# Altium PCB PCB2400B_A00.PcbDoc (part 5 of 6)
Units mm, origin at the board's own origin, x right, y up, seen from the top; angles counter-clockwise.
Board outline 114.9 x 59.9 mm, 6 copper layers (Top Layer, Signal Layer 2, Signal Layer 3, Signal Layer 4, Signal Layer 5, Bottom Layer), stack 1.555 mm thick; 383 components, 308 nets, 1386 pads, 1147 vias.

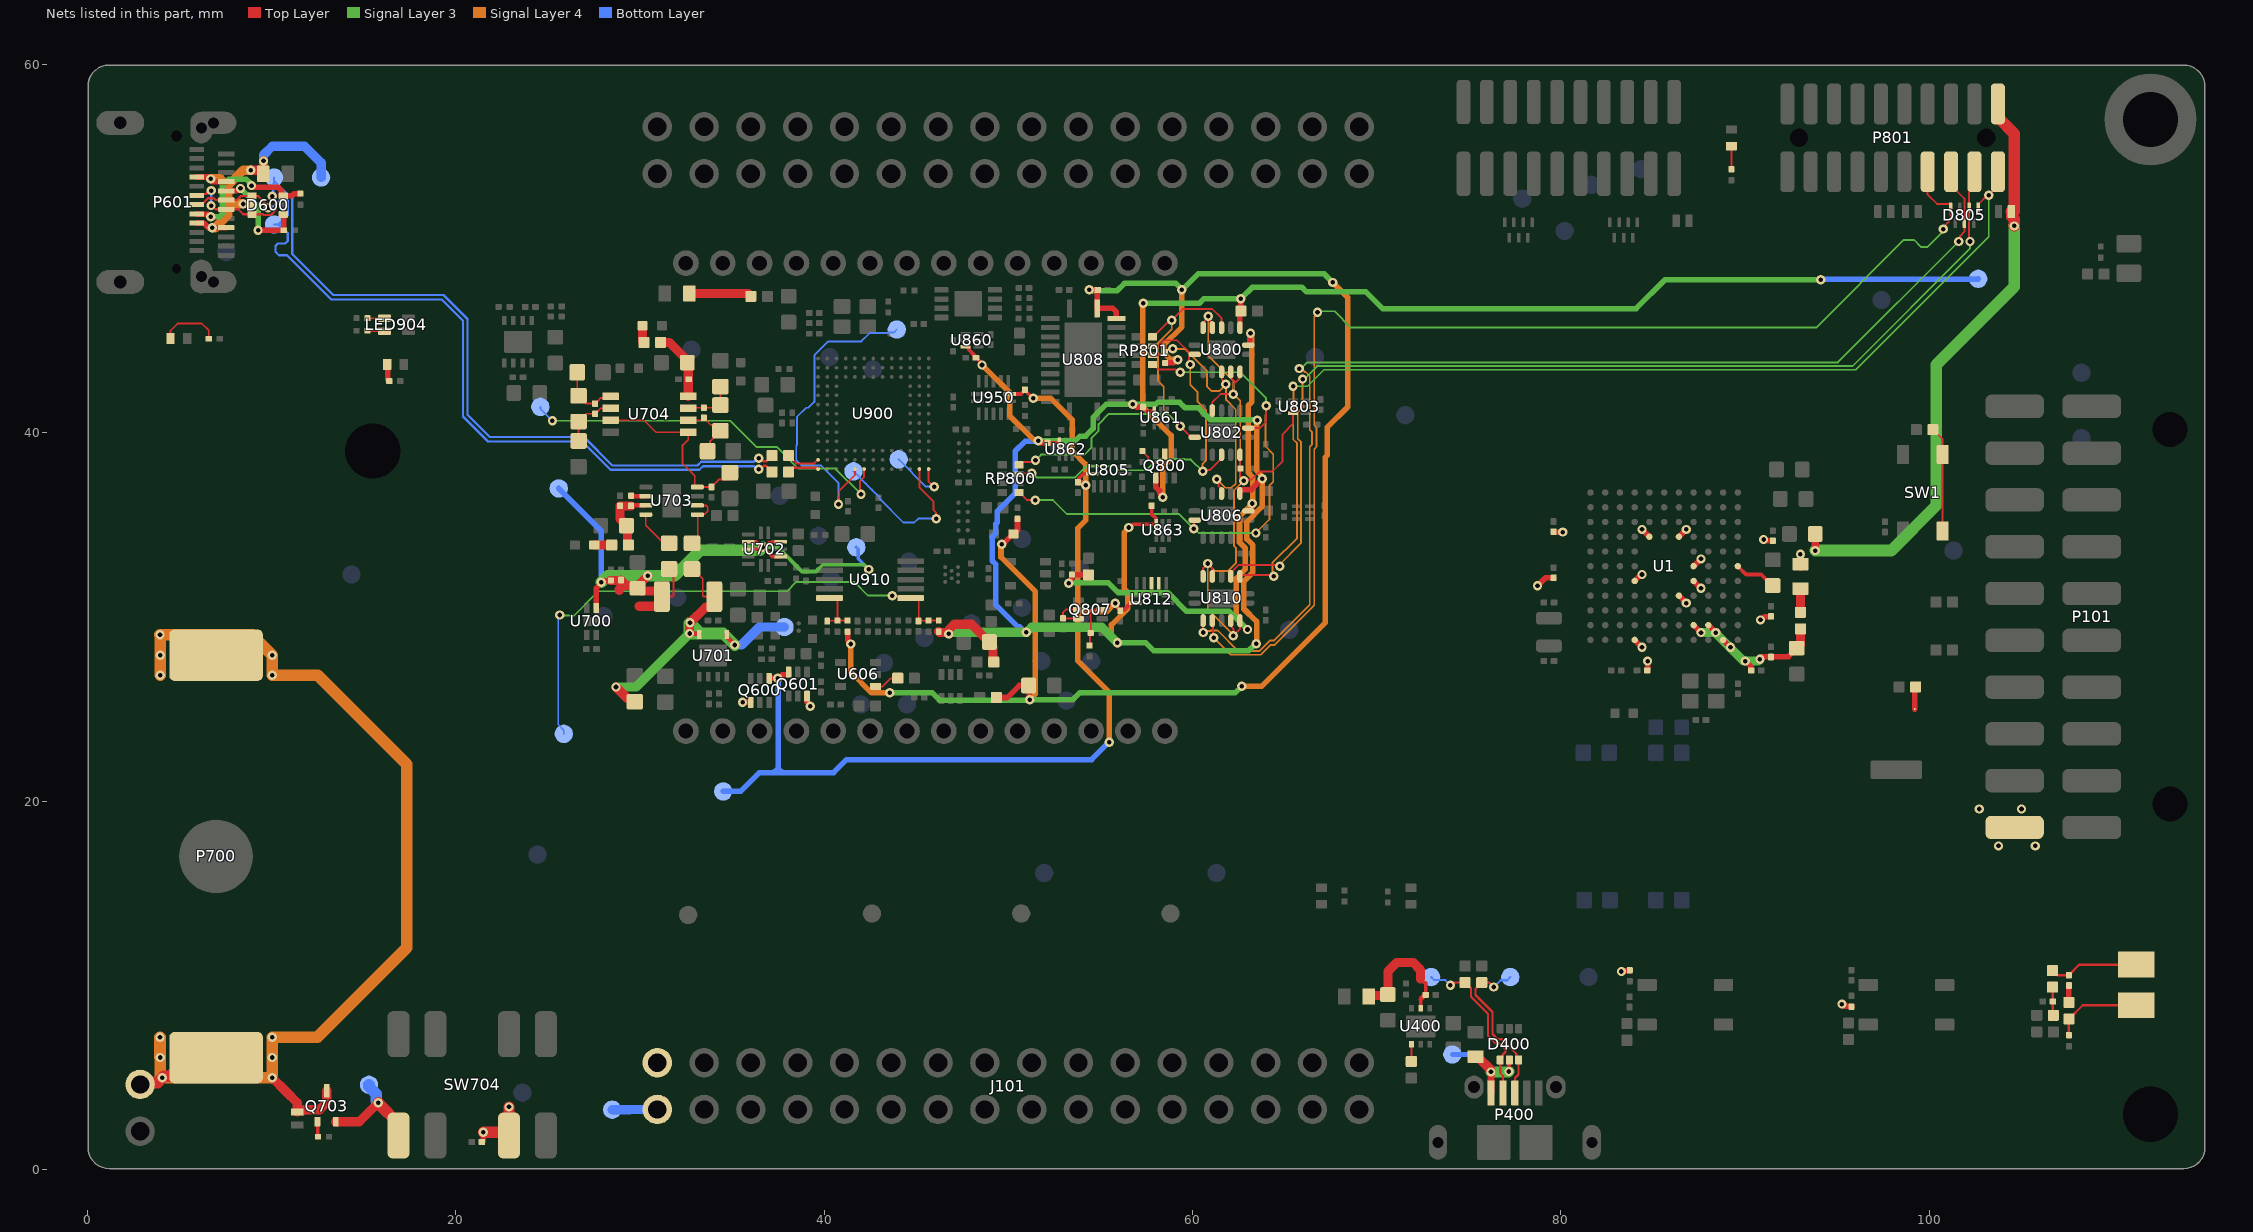
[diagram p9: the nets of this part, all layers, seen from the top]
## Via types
v1: diameter 0.5, hole 0.25, Top Layer to Bottom Layer, tented both sides, 768 vias
v2: diameter 0.508, hole 0.25, Top Layer to Bottom Layer, tented both sides, 379 vias

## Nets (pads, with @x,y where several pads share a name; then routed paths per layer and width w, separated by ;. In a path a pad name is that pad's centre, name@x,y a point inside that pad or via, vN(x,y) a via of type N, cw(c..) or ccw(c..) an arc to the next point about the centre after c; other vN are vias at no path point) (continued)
N16939638: TPJ900.1 U900.A2 | length 8.8
  Top Layer w0.1: U900.A2@45.175,38.025 45.175,37.031 45.741,36.466 45.947,36.259 45.947,35.803 46.07,35.68 46.07,35.35 v2(46.086,35.334)
  Bottom Layer w0.1: TPJ900.1@41.607,37.9 42.27,37.237 42.6,36.907 43.018,36.488 43.018,36.464 43.018,36.409 44.305,35.122 44.897,35.122 45.109,35.334 v2(46.086,35.334)
N16939640: TPJ901.1 U900.A1 | length 3.6
  Top Layer w0.1: U900.A1@45.675,37.966 45.675,37.346 45.934,37.088 45.934,37.072 v2(45.972,37.072)
  Bottom Layer w0.1: TPJ901.1@44.05,38.55 45.53,37.07 45.905,37.07 45.925,37.05 45.947,37.072 v2(45.972,37.072)
N16940103: TPJ908.1 U900.A9 | length 17.6
  Top Layer w0.1: v2@40.781,36.128 40.786,36.134 40.786,36.466 40.827,36.507 40.827,36.839 ; 40.96,36.971 40.827,36.839 ; U900.A9@41.675,38.025 41.675,37.687 40.827,36.839
  Bottom Layer w0.1: v2(40.786,36.123) 40.786,37.253 39.816,38.223 38.777,38.223 38.489,38.511 38.489,39.301 38.525,39.337 38.525,40.85 39.025,41.35 39.154,41.35 39.475,41.671 39.475,44.2 40.225,44.95 42.025,44.95 42.485,45.41 43.441,45.41 43.46,45.428 43.778,45.428 TPJ908.1@43.95,45.6
N16942491: R902.2 U900.B13 | length 1.9
  Top Layer w0.12: R902.2@38.075,38.75 38.493,38.332 39.472,38.332 39.666,38.525 U900.B13@39.675,38.525
N16942503: R904.2 U900.A13 | length 1.7
  Top Layer w0.12: R904.2@38.075,37.875 38.292,38.092 39.587,38.092 39.653,38.025 U900.A13@39.675,38.025
N16943456: TPJ902.1 U900.A8 | length 20.9
  Top Layer w0.1: v2(42.007,36.66) 41.95,36.717 41.95,37.375 42.175,37.6 U900.A8@42.175,38.025
  Signal Layer 3 w0.1: v1(25.254,40.644) 34.906,40.644 36.325,39.225 37.425,39.225 38.6,38.05 40.618,38.05 v2@42.007,36.661
  Bottom Layer w0.1: TPJ902.1@24.6,41.4 24.6,41.298 v1(25.254,40.644)
N16944010: LED903.2 R912.2 | length 0.7
  Top Layer w0.305: LED903.2@16.325,43.5 16.325,42.875 16.382,42.818 16.382,42.808 16.39,42.8 R912.2@16.4,42.8
N16966205: LED904.2 R920.2 | length 0.9
  Top Layer w0.1: R920.2@15.222,46.215 15.237,46.2 15.425,46.2 15.435,46.21 LED904.2@16.139,46.21
N16966207: LED904.1 R919.2 | length 0.9
  Top Layer w0.1: R919.2@15.222,45.531 15.228,45.525 15.45,45.525 15.465,45.51 LED904.1@16.139,45.51
N16966211: LED901.1 R903.2 | length 3.3
  Top Layer w0.1: LED901.1@4.525,45.125 4.525,45.538 4.912,45.925 6.225,45.925 6.6,45.55 R903.2@6.6,45.1
N16966215: LED900.1 R900.2 | length 1.3
  Top Layer w0.1: R900.2@89.25,54.3 LED900.1@89.25,55.55
N16996446: Q807.5 Q807.6 R838.1 | length 2
  Top Layer w0.1: Q807.6@53.8,29.9 53.787,29.913 52.987,29.913 R838.1@52.975,29.925 52.975,30.245 53.13,30.4 Q807.5@53.8,30.4
N16997087: Q807.2 R839.2 R841.1 | length 2.5
  Top Layer w0.1: R841.1@54.411,28.445 54.443,28.477 54.443,29.093 R839.2@54.475,29.125 54.475,30.2 54.675,30.4 Q807.2@55.1,30.4
N17012885: L900.2 R130.1 | length 3.3
  Top Layer w0.5: L900.2@32.69,47.55 35.875,47.55 R130.1@35.975,47.45
N17206837: C198.1 L100.1 R197.2 | length 4.9
  Top Layer w0.127: R197.2@106.677,10.8 106.933,10.544 C198.1@107.568,10.544 107.568,10.564 108.129,11.125 L100.1@111.222,11.125
N17206841: L100.2 R195.1 R196.2 | length 4.8
  Top Layer w0.127: R196.2@107.568,7.293 107.568,8.171 R195.1@107.572,8.175 108.322,8.925 L100.2@111.222,8.925
N17206845: C198.2 R195.2 | length 0.9
  Top Layer w0.3: C198.2@107.568,9.994 107.57,9.992 107.57,9.077 R195.2@107.572,9.075
N17206847: C199.1 R197.1 R198.2 | length 1.5
  Top Layer w0.127: R197.1@106.677,9.9 106.7,9.877 C199.1@106.7,9.126 106.7,8.397 R198.2@106.722,8.375
N17234269: C200.1 R246.2 | length 1.2
  Top Layer w0.3: C200.1@99.2,25 99.2,26.15 R246.2@99.25,26.2
N17262372: C729.1 R718.2 U703.4 U704.3 U704.5 | length 9.9
  Top Layer w0.1: U704.3@28.42,40.675 30.227,40.675 30.877,40.025 U704.5@32.631,40.025 32.631,39.627 32.325,39.321 32.325,38.325 32.983,37.667 32.983,37.124 33.057,37.05 U703.4@33.125,37.05 C729.1@33.9,37.05 33.9,37.07 34.28,37.45 R718.2@34.925,37.45
N17262509: R709.1 U703.1 U703.2 | length 3.2
  Top Layer w0.1: R709.1@32.832,34 33.147,34.315 33.147,35.528 U703.1@33.125,35.55 33.163,35.588 33.537,35.588 33.687,35.738 33.687,35.96 33.597,36.05 U703.2@33.125,36.05
N17262517: C710.2 U703.6 | length 0.8
  Top Layer w0.25: C710.2@29.525,36.575 29.55,36.55 U703.6@30.325,36.55
N17262549: R710.1 U703.8 | length 2.2
  Top Layer w0.1: U703.8@30.325,35.55 30.325,34.975 R710.1@31.3,34
  Top Layer w0.127: R710.1@31.3,34 R710.1@31.59,34
N17262561: L700.2 R717.1 | length 1
  Top Layer w0.5: L700.2@27.525,33.9 R717.1@28.475,33.9
N17262689: C766.1 R765.1 R767.2 U704.2 | length 3.1
  Top Layer w0.1: R767.2@26.675,39.55 R765.1@26.675,40.6 27.1,41.025 C766.1@27.575,41.025 27.875,41.325 U704.2@28.42,41.325
N17262695: C766.2 R764.1 R765.2 U704.1 | length 3.4
  Top Layer w0.1: R764.1@26.6,43.275 26.6,42.075 R765.2@26.675,42 27.1,41.575 C766.2@27.575,41.575 27.575,41.595 27.685,41.705 27.705,41.705 27.884,41.884 28.328,41.884 U704.1@28.42,41.975
N17262717: C770.1 R769.1 R771.2 U704.6 | length 3.5
  Top Layer w0.1: U704.6@32.631,40.675 33.35,40.675 C770.1@33.475,40.8 33.475,40.78 33.585,40.67 33.605,40.67 33.863,40.412 34.063,40.412 R769.1@34.375,40.1 33.816,39.541 33.816,39.141 R771.2@33.675,39
N17262723: C770.2 R768.1 R769.2 U704.7 | length 2.8
  Top Layer w0.1: U704.7@32.631,41.325 32.656,41.35 C770.2@33.475,41.35 34.225,41.35 R769.2@34.375,41.5 R768.1@34.375,42.5
N17263058: C730.1 C731.1 R731.1 U704.8 | length 3.9
  Top Layer w0.5: R731.1@31.125,44.9 31.6,44.9 32.575,43.925 C731.1@32.575,43.8 32.63,43.745 32.63,42.031 32.575,42.031 U704.8@32.631,41.975
N17263074: L704.2 R731.2 | length 0.9
  Top Layer w0.5: L704.2@30.15,45.8 30.15,44.975 R731.2@30.225,44.9
N17356200: Q800.2 R815.1 | length 1.9
  Top Layer w0.1: R815.1@57.276,39.006 57.276,38.996 57.605,38.667 57.605,38.57 57.825,38.35 58.175,38.35 58.5,38.675 Q800.2@58.5,38.85
N17454530: D703.1 P700.1 Q703.3 ST701.2 | length 60.2
  Top Layer w0.508: v2(10.046,4.981) 10.793,4.234 11.403,3.625 D703.1@11.403,3.123 11.457,3.177 11.701,3.177 11.772,3.249 12.618,3.249 13,3.631 Q703.3@13,4.275
  Top Layer w0.635: ST701.2@2.875,4.62 2.98,4.725 3.83,4.725 v2(4.087,4.981) 4.166,5.061 4.521,5.061 5.538,6.078 8,6.078 P700.1@8.328,5.75 ; P700.1@7.846,27.922 P700.1@8.067,28.143
  Signal Layer 4 w0.635: v2(3.958,7.181) 3.958,6.085 v2(3.962,6.081) 3.962,5.106 v2(4.087,4.981) v2(10.046,4.981) v2(10.046,6.081) v2(10.046,7.181) 12.5,7.181 17.352,12.033 17.352,21.996 12.523,26.825 v2(10.046,26.825) v2(10.046,27.925) 8.946,29.025 v2(3.958,29.025) 3.962,29.021 v2(3.962,27.925) v2(3.962,26.825)
N17454556: Q703.2 SW704.1 TP156.1 | length 6
  Top Layer w0.508: Q703.2@13.5,2.6 14.775,2.6 v1(15.8,3.625)
  Top Layer w0.635: v1(15.8,3.625) 15.8,3.6 16.9,2.5 16.9,2.325 SW704.1@16.9,1.85
  Bottom Layer w0.635: TP156.1@15.3,4.6 15.3,4.501 15.7,4.101 v1@15.7,3.725
N17454707: Q703.1 R792.2 | length 0.8
  Top Layer w0.203: Q703.1@12.5,2.6 12.517,2.583 12.517,1.799 R792.2@12.534,1.782
N17455720: L1.2 R2.1 | length 1.2
  Top Layer w0.5: L1.2@92.975,31.45 93,31.425 R2.1@93,30.25
N17455730: C3.1 C4.1 C5.1 R2.2 U1.K8 U1.K9 U1.L10 | length 9.7
  Top Layer w0.3: U1.K8@87.2,29.55 v1(87.601,29.149) ; U1.K9@88,29.55 v1(88.401,29.149) ; U1.L10@88.8,28.75 v1(89.201,28.349) ; v1(90,27.6) 90.019,27.6 90.295,27.324 90.295,27.11 90.305,27.1 C4.1@90.325,27.1 ; v1(90.8,27.7) 90.925,27.825 C5.1@91.4,27.825 91.475,27.825 92.325,27.825 ; 92.35,27.85 92.325,27.825 ; C3.1@92.8,28.3 92.325,27.825
  Top Layer w0.5: C3.1@92.8,28.3 93,28.5 R2.2@93,29.35
  Signal Layer 3 w0.5: v1(87.601,29.149) v1(88.401,29.149) 88.401,29.116 89.917,27.6 v1(90,27.6) 90.7,27.6 v1(90.8,27.7)
N17455955: C16.1 U1.F11 | length 2.4
  Top Layer w0.203: U1.F11@89.6,32.75 90.05,32.3 90.875,32.3 91.47,31.705 C16.1@91.52,31.705
N17456044: R7.2 SW1.3 SW1.4 | length 5.7
  Top Layer w0.1: R7.2@100.187,40.162 100.717,39.631 SW1.4@100.717,38.814 SW1.3@100.717,34.664
N17457251: D400.6 P400.3 R405.1 TPJ403.1 | length 9.2
  Top Layer w0.12: v1(76.351,9.911) 76.112,10.15 R405.1@75.7,10.15 75.36,9.81 75.36,9.475 76.281,8.554 76.281,7.363 76.57,7.074 76.788,7.074 77.572,6.289 77.572,6.077 D400.6@77.7,5.95 77.7,5.16 77.508,4.968 77.508,4.165 P400.3@77.5,4.157
  Bottom Layer w0.12: v1@76.35,9.9 76.728,10.278 77.079,10.278 TPJ403.1@77.25,10.449
N17457255: D400.4 P400.2 R406.1 TPJ404.1 | length 9.3
  Top Layer w0.12: v1(74,10) 74.103,10 74.253,10.15 R406.1@74.8,10.15 75.12,9.83 75.12,9.375 76.041,8.455 76.041,7.264 76.471,6.834 76.689,6.834 76.99,6.533 76.99,6.382 76.827,6.22 76.827,6.077 D400.4@76.7,5.95 76.7,5.236 76.85,5.085 P400.2@76.85,4.157
  Bottom Layer w0.12: TPJ404.1@72.95,10.449 73.115,10.284 73.716,10.284 v1(74,10)
N17457259: D400.5 L401.1 P400.1 TPJ405.1 | length 8.8
  Top Layer w0.2: v1(77.175,5.325) 77.175,5.925 D400.5@77.2,5.95
  Top Layer w0.3: L401.1@75.366,6.13 75.41,6.13 75.595,5.945 75.595,5.905 v1(76.2,5.3) 76.2,4.81 76.195,4.805 P400.1@76.195,4.15
  Top Layer w0.4: P400.1@76.2,4.157 v1(76.2,5.3)
  Top Layer w0.5: L401.1@75.41,6.13 75.471,6.13 76.2,5.401 v1(76.2,5.3)
  Signal Layer 3 w0.6: v1(76.2,5.3) 77.15,5.3 v1(77.175,5.325)
  Bottom Layer w0.25: TPJ405.1@74.101,6.248 75.252,6.248 v1(76.2,5.3)
N17457715: C419.1 C423.1 L402.2 U400.2 | length 7.2
  Top Layer w0.2: 72.378,10.35 72.585,10.143 72.648,10.143 72.659,10.132 C419.1@72.659,9.485 ; U400.2@72.387,8.751 72.387,9.233 72.387,9.307 72.504,9.425 C419.1@72.579,9.425
  Top Layer w0.254: 72.387,9.233 72.579,9.425 72.639,9.485 C419.1@72.659,9.485
  Top Layer w0.5: L402.2@69.565,9.4 69.616,9.451 C423.1@70.651,9.451 ; C423.1@70.605,9.502 70.605,10.755 71.087,11.237 71.978,11.237 72.378,10.837 72.378,10.35
N17457806: R408.2 U400.4 | length 0.9
  Top Layer w0.102: R408.2@71.874,5.868 71.874,6.074 71.887,6.087 U400.4@71.887,6.801
N17631739: R679.1 U606.1 | length 1.4
  Top Layer w0.1: U606.1@42.8,26.225 43.175,26.225 43.6,26.65 R679.1@44,26.65
SI_HEADER_ENABLE: R807.1 U800.5 U800.6 U800.12 U800.13 U802.5 U802.13 U803.3 U810.5 U810.6 U810.12 U810.13 | length 36.3
  Top Layer w0.1: U810.6@60.575,32.2 60.575,32.65 v2(60.825,32.9) 61.075,32.65 U810.5@61.075,32.2 ; U800.6@60.575,45.7 60.575,45.954 60.85,46.229 v2(60.85,46.325) 60.928,46.247 60.928,46.101 61.075,45.954 U800.5@61.075,45.7 ; U802.5@61.075,41.2 61.075,41.65 61.518,42.093 v2@62.082,42.093 ; U810.12@62.075,29.8 62.113,29.762 62.113,29.462 62.22,29.355 v2(62.22,28.976) ; U800.12@62.075,43.3 62.113,43.262 62.113,42.962 62.338,42.738 ; v2(62.218,42.093) 62.218,42.618 62.338,42.738 ; v2@62.25,29 62.575,29.325 U810.13@62.575,29.8 ; U802.13@62.575,38.8 62.575,37.698 62.775,37.498 v2(62.775,37.387) 62.84,37.453 63.179,37.453 63.619,37.893 64.343,37.893 64.888,38.438 64.888,39.913 65.45,40.475 U803.3@65.45,41.05 ; U800.13@62.575,43.3 62.537,43.262 62.537,42.937 62.338,42.738
  Signal Layer 4 w0.1: v2(60.85,46.325) 60.85,44.175 62.218,42.807 v2(62.218,42.093) 62.59,41.721 62.59,37.535 62.738,37.387 v2(62.775,37.387) ; v2(62.22,28.976) 62.247,29.003 60.825,30.425 v2(60.825,32.9) 61.243,32.482 61.907,32.482 62.368,32.943 62.368,33.733 62.25,33.851 62.25,36.862 v2@62.762,37.373
SI_VCOM_CTS: D805.4 P801.8 U810.10 | length 65.1
  Top Layer w0.1: U810.10@61.075,29.8 61.112,29.763 61.112,28.912 v2(61.15,28.875) ; P801.8@99.825,54 99.9,53.925 99.9,52.925 100.414,52.411 101.105,52.411 101.15,52.366 D805.4@101.15,52.215 101.15,51.55 100.75,51.15 v1(100.75,51.05)
  Signal Layer 3 w0.1: v1(66.784,46.541) 66.775,46.55 66.816,46.591 67.709,46.591 68.6,45.7 93.85,45.7 98.611,50.461 99.161,50.461 99.55,50.072 99.886,50.072 100.673,50.86 100.673,50.973 v1(100.75,51.05)
  Signal Layer 4 w0.1: v2(61.15,28.875) 62.083,27.942 63.711,27.942 64.252,28.483 64.466,28.483 66.606,30.623 66.606,39.107 66.731,39.232 66.731,40.291 66.606,40.417 66.606,46.282 66.784,46.461 v1(66.784,46.541)
SI_VCOM_RTS: D805.6 P801.6 U810.9 | length 63.6
  Top Layer w0.1: U810.9@60.575,29.8 60.577,29.798 60.577,29.156 v2(60.579,29.154) ; P801.6@101.175,53.775 101.175,53.435 101.9,52.71 D805.6@101.9,51.385 ; v1(101.596,50.375) 101.666,50.445 101.666,50.671 101.9,50.905 D805.6@101.9,51.3
  Signal Layer 3 w0.1: v1(65.79,43.477) 65.888,43.477 66.222,43.811 95.032,43.811 v1(101.596,50.375)
  Signal Layer 4 w0.1: v2(60.579,29.154) 60.657,29.232 60.951,29.232 60.987,29.268 61.357,29.268 62.483,28.142 63.628,28.142 64.2,28.713 64.413,28.713 66.362,30.662 66.362,39.238 66.487,39.363 66.487,40.021 66.362,40.146 66.362,43.066 66.134,43.294 66.081,43.294 65.898,43.477 v1(65.79,43.477)
SI_VCOM_RXD: D805.1 P801.2 U810.2 | length 58.6
  Top Layer w0.1: U810.2@62.575,32.2 62.65,32.275 64.356,32.275 v2(64.417,32.215) ; D805.1@102.65,52.215 102.65,52.385 103.149,52.884 v2(103.221,52.884) 103.221,52.912 103.775,53.466 P801.2@103.775,54.1
  Signal Layer 3 w0.1: v1(65.461,42.516) 66.241,42.516 67.136,43.411 95.999,43.411 103.221,50.634 v2(103.221,52.884)
  Signal Layer 4 w0.1: v2(64.417,32.215) 64.339,32.293 64.339,32.931 65.674,34.267 65.674,39.419 65.465,39.627 65.465,41.216 65.475,41.226 v1@65.475,42.45
SI_VCOM_TXD: D805.2 P801.4 U810.3 | length 57.3
  Top Layer w0.1: U810.3@62.075,32.2 62.075,32.4 62.5,32.825 64.653,32.825 v2(64.732,32.747) ; D805.2@102.15,52.215 102.15,53.064 102.425,53.339 P801.4@102.425,54.225 ; D805.2@102.155,52.13 102.155,50.42 v2(102.2,50.375)
  Signal Layer 3 w0.1: v1(65.973,42.905) 66.055,42.905 66.761,43.611 95.823,43.611 102.2,49.989 v2(102.2,50.375)
  Signal Layer 4 w0.1: v2(64.732,32.747) 64.732,32.845 65.881,33.994 65.881,39.495 65.709,39.667 65.709,41.115 65.975,41.38 65.975,42.903 v1(65.973,42.905)
TCK_SWCLK: RP800.3 RP801.3 U800.8 U802.11 | length 22.2
  Top Layer w0.1: RP800.3@50.575,37.75 50.6,37.775 51.25,37.775 v2(51.275,37.8) ; RP801.3@57.925,44.7 RP801.3@57.825,44.7 57.855,44.73 58.14,44.73 58.428,45.018 59.157,45.018 59.925,44.25 U800.8@59.937,44.25 ; v2(59.878,43.702) 59.81,43.77 59.81,44.123 U800.8@59.937,44.25 ; U800.8@60.125,44.25 U800.8@59.937,44.25 ; v2(60.55,37.9) 60.628,37.978 60.953,37.978 61.575,38.6 U802.11@61.575,38.8
  Signal Layer 3 w0.1: v2(51.275,37.8) 51.313,37.8 51.538,37.575 53.631,37.575 54.249,38.193 55.753,38.193 55.989,37.957 57.494,37.957 58.101,38.564 59.579,38.564 59.604,38.539 59.911,38.539 v2(60.55,37.9)
  Signal Layer 4 w0.1: v2(59.878,43.702) 59.878,42.607 60.266,42.219 60.266,41.703 60.725,41.244 60.725,38.484 60.55,38.309 v2(60.55,37.9)
TDI: RP800.1 RP801.1 U802.1 U806.8 | length 31
  Top Layer w0.1: RP800.1@50.575,36.75 50.625,36.75 51.035,36.34 v2(51.473,36.34) ; RP801.1@57.825,43.7 57.875,43.7 58.141,43.434 59.062,43.434 59.221,43.275 v2(59.325,43.275) ; v2@60.125,34.875 60.075,34.925 60.075,35.2 U806.8@60.125,35.25 ; U802.1@63.025,40.25 63.644,40.25 63.99,40.596 63.99,41.446 v2(63.996,41.451)
  Signal Layer 3 w0.1: v2(51.473,36.34) 52.427,36.34 53.189,35.578 59.272,35.578 v2(60.075,34.775) 60.116,34.775 60.338,34.554 v2(63.443,34.554) ; v2(59.325,43.275) 62.6,43.275 63.996,41.879 v2(63.996,41.451)
  Signal Layer 4 w0.1: v2(63.443,34.554) 64.175,35.286 64.175,37.124 64.386,37.335 64.386,38.834 63.961,39.258 63.961,40.962 63.996,40.997 v2(63.996,41.451)
TDO_SWO: R801.1 RP801.2 U800.11 U806.4 | length 14.3
  Top Layer w0.1: RP801.2@57.825,44.2 58.175,44.2 58.237,44.262 58.404,44.262 58.514,44.372 R801.1@58.514,44.382 58.603,44.472 58.847,44.472 v2(58.925,44.55) ; v2(61.325,37.475) 61.403,37.397 61.403,37.126 61.575,36.954 U806.4@61.575,36.7 ; U800.11@61.575,43.3 61.588,43.287 61.588,42.889 61.808,42.669 v2(61.808,42.626)
  Signal Layer 4 w0.1: v2(58.925,44.55) 59.586,44.55 60.793,43.343 60.793,42.501 61.037,42.257 61.457,42.257 61.817,42.617 v2(61.808,42.626) ; v2(61.325,37.475) 61.325,37.469 61.787,37.007 62.113,37.007 62.343,37.237 62.343,41.257 61.825,41.775 v2@61.825,42.575
TMS_SWDIO: RP800.4 RP801.4 U800.4 U802.8 | length 23.2
  Top Layer w0.1: RP800.4@50.575,38.25 50.725,38.4 v2@51.275,38.4 ; RP801.4@57.825,45.2 57.875,45.2 58.775,46.1 v2(58.875,46.1) 59.493,46.718 61.057,46.718 61.575,46.2 U800.4@61.575,45.7 ; v2(59.325,40.35) 59.925,39.75 U802.8@60.125,39.75
  Signal Layer 3 w0.1: v2@51.55,38.465 51.55,38.575 51.782,38.807 54.138,38.807 54.514,39.184 54.514,39.706 54.9,40.092 54.9,40.464 55.451,41.015 58.66,41.015 v2(59.325,40.35)
  Signal Layer 4 w0.1: v2(58.875,46.1) 58.875,45.621 58.132,44.878 58.132,42.801 58.443,42.491 58.443,41.232 v2(59.325,40.35)
  other v2: 51.475,38.5
USB_DM: D600.6 P601.A7 P601.B7 R902.1 TPJ612.1 | length 46
  Top Layer w0.106: v1(6.727,52.323) v1@6.786,52.323
  Top Layer w0.12: P601.B7@5.95,52.875 6.025,52.95 6.451,52.95 6.638,53.137 v1(6.741,53.137) ; v1@6.786,52.323 6.984,52.125 P601.A7@7.55,52.125 8.198,52.125 8.473,51.85 D600.6@8.95,51.85 9.542,51.85 9.582,51.81 9.984,51.81 10.218,52.044 10.218,52.573 10.05,52.741 v1(10.05,52.828) ; v1(36.45,38.613) 36.545,38.613 36.71,38.447 36.872,38.447 R902.1@37.175,38.75
  Bottom Layer w0.106: v1(6.727,52.323) v1@6.734,52.33 ; v1@6.734,53.13 v1(6.741,53.137)
  Bottom Layer w0.12: v1@6.734,52.33 v1@6.734,53.13 ; v1(10.05,52.828) 10.099,52.877 10.099,53.494 10.149,53.543 TPJ612.1@10.149,53.677 ; TPJ612.1@10.149,53.851 TPJ612.1@10.149,53.677 ; v1(36.45,38.613) 36.382,38.613 36.19,38.421 33.327,38.421 33.127,38.221 28.511,38.221 26.973,39.759 21.861,39.759 20.643,40.977 20.643,46.174 19.345,47.472 13.356,47.472 11.131,49.697 11.131,52.694 TPJ612.1@10.149,53.677
USB_DP: D600.4 P601.A6 P601.B6 R904.1 TPJ611.1 | length 45.1
  Top Layer w0.12: P601.B6@5.95,52.375 6.215,52.375 6.562,52.722 6.892,52.722 6.989,52.625 P601.A6@7.55,52.625 8.127,52.625 8.352,52.85 D600.4@8.95,52.85 8.961,52.839 9.288,52.839 9.819,52.308 v1(9.819,52.209) ; v1(36.45,38.013) 36.553,38.013 36.745,38.205 36.845,38.205 R904.1@37.175,37.875
  Bottom Layer w0.12: v1(9.819,52.209) 9.89,52.28 10.116,52.28 10.574,52.738 10.748,52.738 10.891,52.595 10.891,51.805 TPJ611.1@10.387,51.301 ; TPJ611.1@10.149,51.301 TPJ611.1@10.387,51.301 ; v1(36.45,38.013) 36.358,38.013 36.19,38.181 33.426,38.181 33.226,37.981 28.412,37.981 26.874,39.519 21.762,39.519 20.403,40.878 20.403,46.074 19.245,47.232 13.257,47.232 10.854,49.635 10.408,49.635 10.225,49.819 10.225,50.136 10.363,50.274 10.764,50.274 10.891,50.401 10.891,50.842 10.651,51.082 10.606,51.082 TPJ611.1@10.387,51.301
USBC_CC1: D600.1 P601.A5 R621.2 | length 5.3
  Top Layer w0.305: P601.A5@7.55,53.125 v1@8.136,53.125 ; v1(9.279,50.987) R621.2@10.66,50.987 ; R621.2@10.67,51.13 D600.1@10.67,51.83
  Signal Layer 3 w0.305: v1(8.324,53.26) 9.279,52.305 v1(9.279,50.987)
USBC_CC2: D600.3 P601.B5 R620.2 | length 8
  Top Layer w0.305: P601.B5@5.95,51.875 5.967,51.858 6.554,51.858 6.688,51.723 v1(6.714,51.723) ; v1(8.922,53.412) 8.975,53.412 9.068,53.319 10.374,53.319 10.552,53.141 10.552,52.885 10.587,52.85 11.125,52.85 11.241,52.966 11.567,52.966 R620.2@11.575,52.975 R620.2@11.575,52.975
  Signal Layer 3 w0.305: v1(6.714,51.723) 7.182,51.723 7.344,51.885 7.344,53.406 7.689,53.751 8.646,53.751 8.825,53.573 8.825,53.562 8.922,53.465 v1(8.922,53.412)
USBC_VBUS: D600.5 L600.1 P601.A4 P601.A9 P601.B4 P601.B9 TPJ613.1 | length 16.7
  Top Layer w0.305: P601.B4@5.95,51.375 6.333,51.375 6.583,51.125 v1(6.786,51.125) P601.A9@7.55,51.125 ; P601.B9@5.95,53.875 6.575,53.875 6.675,53.775 v1(6.705,53.775) 6.705,53.745 6.825,53.625 P601.A4@7.55,53.625 ; v1(8.477,52.411) 8.507,52.38 8.92,52.38 D600.5@8.95,52.35
  Top Layer w0.508: v1(8.878,54.242) 8.884,54.236 9.479,54.236 9.479,54.131 L600.1@9.56,54.05 9.575,54.065 v1(9.575,54.75)
  Signal Layer 4 w0.508: v1(6.705,53.775) 7.232,53.775 7.486,53.521 7.632,53.375 ; v1(6.786,51.125) 6.791,51.13 6.96,51.13 7.632,51.803 7.632,52.721 ; v1(8.477,52.411) 8.464,52.424 7.93,52.424 7.632,52.721 ; v1(8.878,54.242) 8.468,54.242 7.632,53.406 7.632,53.375 ; 7.632,52.721 7.632,53.375
  Bottom Layer w0.305: v1(6.786,51.125) 6.804,51.143 v1@6.804,51.183
  Bottom Layer w0.508: v1(9.575,54.75) 9.575,55.07 10.055,55.55 11.8,55.55 12.699,54.651 TPJ613.1@12.699,53.851
V_SW: C800.1 C828.1 C950.1 Q600.4 Q601.6 TPJ608.1 U805.14 U812.14 U950.14 | length 56.9
  Top Layer w0.2: U950.14@50.085,42.1 50.695,42.1 C950.1@50.9,42.305 ; C950.1@50.9,42.325 C950.1@50.9,42.305 ; v2(51.35,41.864) 51.341,41.864 C950.1@50.9,42.305 ; C800.1@53.775,37.3 53.835,37.36 53.835,37.526 54.079,37.77 U805.14@54.565,37.77 ; v2@55.859,30.561 C828.1@56.075,30.345 ; C828.1@56.075,30.325 C828.1@56.075,30.345 ; U812.14@56.89,30.75 56.65,30.75 56.305,30.405 56.135,30.405 C828.1@56.075,30.345
  Top Layer w0.3: Q600.4@37.013,26.66 37.013,26.664 37.49,26.664 v2(37.494,26.667) 37.55,26.667 37.733,26.85 38.075,26.85 Q601.6@38.075,27 ; C800.1@53.775,37.3 53.775,37.28 53.785,37.27 v2@54.02,37.27
  Signal Layer 4 w0.3: v2(51.35,41.864) 52.315,41.864 53.482,40.697 53.482,38.996 54.196,38.282 v2(54.196,37.15) 54.196,35.233 53.768,34.805 53.768,30.465 53.958,30.275 ; v2(55.475,23.2) 55.475,25.919 53.768,27.627 53.768,30.105 53.938,30.275 53.958,30.275 ; v2(55.8,30.75) 55.325,30.275 53.958,30.275
  Bottom Layer w0.3: TPJ608.1@34.525,20.526 35.476,20.526 36.493,21.543 37.269,21.543 ; v2(37.494,26.667) v2@37.55,26.667 ; v2@37.511,26.65 37.511,22.561 37.503,22.553 37.503,21.777 ; v2(55.475,23.2) 54.525,22.25 41.229,22.25 40.522,21.543 37.737,21.543 ; 37.269,21.543 37.503,21.543 ; 37.269,21.543 37.503,21.777 ; 37.503,21.543 37.737,21.543 ; 37.503,21.543 37.503,21.777 ; 37.503,21.777 37.737,21.543
VCOM_CTS: U812.9
VCOM_RTS: U812.10
VCS: C710.1 C714.1 C728.1 R717.2 U703.7 | length 3.7
  Top Layer w0.25: C710.1@29.55,36.05 U703.7@30.325,36.05
  Top Layer w0.3: C710.1@29.525,36.025 C710.1@29.55,36.05
  Top Layer w0.5: R717.2@29.375,33.9 29.325,33.95 29.325,34.9 C714.1@29.275,34.95 29.275,34.975 28.925,35.325 C728.1@28.925,36.025 C710.1@29.525,36.025
VMCU: C6.1 C9.1 C10.1 C13.1 C14.1 C15.1 C706.1 D808.1 J101.1 J101.2 L1.1 P101.2 P801.1 Q600.1 Q601.3 R100.2 R101.2 SW704.3 TP703.1 U1.D5 U1.D7 U1.F8 U1.G4 U1.G8 U1.H7 U1.L4 | length 47.8
  Top Layer w0.3: v2(35.577,25.362) 35.578,25.361 36.013,25.361 Q600.1@36.013,25.365 ; Q601.3@39.075,25.7 39.075,25.381 39.25,25.206 v2(39.25,25.15) ; v1(83.279,10.75) 83.317,10.789 83.704,10.789 83.716,10.801 83.726,10.801 83.736,10.811 R101.2@83.736,10.821 ; U1.L4@84,28.75 v1(84.4,28.349) ; U1.G4@84,31.95 84.35,32.3 v1(84.4,32.3) ; v1(84.4,34.75) U1.D5@84.8,34.35 ; U1.H7@86.4,31.15 v1(86.801,30.749) ; U1.D7@86.401,34.35 v1(86.801,34.75) ; U1.G8@87.2,31.95 v1(87.601,31.549) ; U1.F8@87.2,32.75 87.201,32.75 v1(87.601,33.149) ; v1(91,34.2) 91.075,34.125 C15.1@91.5,34.125 ; v1(95.25,8.984) 95.304,8.984 95.433,8.855 95.759,8.855 95.769,8.845 R100.2@95.769,8.835
  Top Layer w0.305: C706.1@21.425,1.5 21.5,1.575 v1@21.5,2 ; v1(78.725,31.689) 79.161,32.125 C13.1@79.6,32.125 ; C9.1@79.6,34.625 79.625,34.6 v1(80.1,34.6) ; v1@83.317,10.789 83.328,10.8 v1@83.375,10.8 ; C14.1@84.7,27.175 v1(84.7,27.6) ; v1(90.832,29.839) 90.885,29.839 91.051,30.005 91.392,30.005 91.4,30.013 C6.1@91.4,30.025 ; v1(95.25,8.984) v1@95.327,8.906
  Top Layer w0.4: v1(92.998,33.398) 93,33.395 L1.1@93,32.7 ; v1(93.8,33.6) C10.1@93.8,34.4
  Top Layer w0.6: v1@21.518,2.025 22.625,2.025 22.9,1.75 SW704.3@22.9,1.85 v1(22.9,3.4)
  Top Layer w0.635: P801.1@103.779,57.054 104.6,56.233 D808.1@104.6,52 ; D808.1@104.45,52 104.483,51.967 104.483,51.724 104.6,51.606 v1(104.6,51.225)
  Signal Layer 3 w0.635: v1(93.8,33.6) 97.923,33.6 100.368,36.045 100.368,43.693 104.6,47.925 v1(104.6,51.225)
  Bottom Layer w0.5: TP703.1@28.5,3.25 28.501,3.249 29.448,3.249 29.461,3.262 J101.1@30.95,3.262
  other v1: 21.5,2.025 103.747,17.57 105.747,17.57 102.7,19.57 105,19.57
VMCU_BUF: C625.1 C861.1 C863.1 C865.1 C867.1 R630.2 R675.2 U806.2 U860.6 U861.6 U862.6 U863.6 | length 82
  Top Layer w0.2: U860.6@47.674,44.659 47.849,44.659 47.849,44.509 48.165,44.193 48.165,44.124 48.225,44.064 48.265,44.064 48.575,43.754 v2(48.575,43.675) ; C861.1@52.125,39.45 U862.6@52.775,39.45 ; v2(56.539,34.85) 56.623,34.85 56.798,35.025 58.025,35.025 58.025,35.336 57.78,35.581 C867.1@57.78,36.031 ; C865.1@57.302,41.377 57.31,41.377 57.372,41.315 57.372,41.307 57.53,41.15 U861.6@57.925,41.15
  Top Layer w0.3: v2@48.545,43.675 v2(48.575,43.675) ; v2@51.775,39.45 C861.1@52.125,39.45 ; v2(56.75,41.55) 56.806,41.55 56.979,41.377 C865.1@57.302,41.377 ; U806.2@62.575,36.7 62.575,36.894 63.176,36.894 v2(63.782,37.5)
  Top Layer w0.5: R630.2@46.225,29.2 46.273,29.152 v2@46.623,29.152 ; v2(46.775,29.075) 46.777,29.077 46.777,29.305 47.072,29.6 48,29.6 C625.1@48.975,28.625 ; C625.1@48.975,28.6 48.975,28.575 49.17,28.38 49.17,27.591 R675.2@49.212,27.549
  Signal Layer 3 w0.3: v2@51.65,39.525 51.677,39.552 53.63,39.552 53.895,39.818 54.201,39.818 54.6,40.216 54.6,40.825 55.325,41.55 v2(56.75,41.55) 58.009,41.55 58.103,41.644 59.306,41.644 59.607,41.343 60.332,41.343 60.975,40.7 63.475,40.7 63.475,40.67 v1(63.514,40.67) ; v2(55.925,28.6) 57.453,28.6 57.903,28.15 63.024,28.15 63.409,28.535 v2(63.465,28.535)
  Signal Layer 3 w0.5: v2(46.775,29.075) 46.777,29.075 46.863,29.161 v2(50.981,29.161) 50.983,29.161 51.265,29.443 55.069,29.443 55.84,28.671 55.852,28.671 55.923,28.6 v2(55.925,28.6)
  Signal Layer 4 w0.3: v2(48.575,43.675) 50.081,42.169 50.081,40.915 51.404,39.592 51.588,39.592 v2(51.628,39.552) ; v2(55.925,28.6) 55.925,28.656 55.593,28.988 55.593,29.563 56.493,30.463 56.493,31.335 56.282,31.546 56.282,34.57 56.539,34.827 v2(56.539,34.85) ; v2@63.437,28.562 v2(63.465,28.535) ; v2@63.481,28.625 63.475,28.631 63.475,29.75 62.782,30.443 62.782,31.929 63.275,32.422 63.275,33.891 62.95,34.216 62.95,35.16 63.782,35.992 v2(63.782,37.5) ; v1(63.514,40.67) 63.497,40.67 63.475,40.648 63.475,37.95 v2@63.725,37.7
  Bottom Layer w0.3: 49.322,34.659 49.322,34.544 ; v2(50.981,29.161) 50.925,29.161 50.633,29.453 50.522,29.453 49.322,30.653 49.322,32.848 49.122,33.048 49.122,34.344 49.322,34.544 ; v2(51.628,39.552) 51.622,39.546 50.924,39.546 50.368,38.99 50.368,36.705 49.407,35.744 49.407,35.135 49.322,35.05 49.322,34.544
VMCU_R: R701.1 R702.2 R709.2 TP700.1 U701.1 U701.4 | length 20.1
  Top Layer w0.1: R709.2@32.832,32.6 32.883,32.6 33.416,32.067 33.416,31.159 33.475,31.1 R701.1@34.05,31.1
  Top Layer w0.25: v2(32.7,29.1) 32.725,29.075 33.225,29.075 U701.4@33.225,29.05 ; U701.1@34.725,29.05 34.725,28.925 35.15,28.5 v2(35.15,28.475)
  Top Layer w0.5: v1(28.707,26.195) 29.332,25.571 29.55,25.571 R702.2@29.725,25.396 ; v2(32.7,29.1) v2@32.7,29.675 ; v2(32.725,29.675) 33.575,30.525 33.875,30.525 34.05,30.7 R701.1@34.05,31.1
  Signal Layer 3 w0.5: v1(28.707,26.195) 29.795,26.195 v2(32.7,29.1)
  Signal Layer 3 w0.635: v2@32.7,29.65 v2(32.7,29.1) 33.225,29.1 ; v2(32.725,29.675) 33.225,29.175 33.225,29.1 ; v2(35.15,28.475) 34.525,29.1 33.225,29.1
  Bottom Layer w0.508: v2(35.15,28.475) 35.519,28.475 36.494,29.45 TP700.1@37.85,29.45
VMCU_S: C700.1 C701.1 R701.2 R710.2 R760.2 TP701.1 TP705.1 U700.3 U702.2 U702.4 U702.9 U702.10 | length 38.1
  Top Layer w0.1: R701.2@31.2,31.1 31.775,31.1 31.834,31.159 31.834,32.356 R710.2@31.59,32.6
  Top Layer w0.2: U702.10@35.89,33.675 36.492,33.675 36.594,33.777 v2(36.677,33.777) v2@36.699,33.777 ; U702.9@35.89,34.075 36.325,34.075 v2@36.55,33.85 ; U702.2@37.66,33.275 37.201,33.275 v2@36.699,33.777 ; U702.4@37.66,34.075 37.201,34.075 37.146,34.02 37.004,34.02 36.76,33.777 v2@36.699,33.777
  Top Layer w0.3: v2(27.9,31.875) 27.956,31.875 28.036,31.955 28.415,31.955 28.425,31.965 R760.2@28.425,31.975
  Top Layer w0.305: U700.3@27.625,30.475 27.625,31.545 27.9,31.82 v2@27.9,31.825
  Top Layer w0.5: R760.2@28.425,31.975 C701.1@28.975,31.975 ; 28.881,31.446 28.881,31.483 28.975,31.577 C701.1@28.975,31.975 ; C701.1@28.975,32 C701.1@28.975,31.975 ; C700.1@29.9,31.55 30.05,31.7 30.05,31.848 v2(30.431,32.231) v2(30.431,32.231) ; 29.97,30.573 31.077,30.573 31.2,30.696 R701.2@31.2,31.1 31.2,31.225 31.025,31.4 30.025,31.4 29.725,31.7 29.25,31.7 C701.1@28.975,31.975
  Signal Layer 3 w0.2: v2(36.677,33.777) 37.495,33.777 38.806,32.466 39.566,32.466 39.925,32.825 42.165,32.825 42.411,32.579 v1(42.432,32.579)
  Signal Layer 3 w0.635: v2(27.9,31.875) 28.256,32.231 v2(30.431,32.231) 31.889,32.231 33.282,33.624 36.524,33.624 v2(36.677,33.777)
  Bottom Layer w0.2: TP705.1@41.75,33.775 41.859,33.666 41.859,33.152 v1(42.432,32.579)
  Bottom Layer w0.305: TP701.1@25.6,36.975 27.9,34.675 v2(27.9,31.875)
VMCU_SENSE: C632.1 R630.1 R631.2 TP708.1 U910.6 | length 29.4
  Top Layer w0.1: v2(43.703,31.153) 43.767,31.089 44.636,31.089 U910.6@44.7,31.025 45.043,31.025 45.143,30.925 45.143,29.793 C632.1@45.125,29.775 45.138,29.787 45.663,29.787 R631.2@45.675,29.8 R630.1@46.225,29.8
  Signal Layer 3 w0.1: v1@25.741,30.075 26.433,30.075 27.75,31.392 37.992,31.392 38.501,31.901 41.638,31.901 42.386,31.153 v2(43.703,31.153)
  Bottom Layer w0.1: v1@25.575,30.067 25.575,24.159 25.875,23.859 TP708.1@25.875,23.65
  other v1: 25.65,30.1
VTARGET: R629.2 R691.1 U800.1 U806.1 | length 30.7
  Top Layer w0.3: v2(53.275,31.825) 53.275,31.881 53.44,32.046 53.44,32.29 53.441,32.292 54.342,32.292 R691.1@54.351,32.283 ; R629.2@53.46,32.319 R629.2@53.46,32.32 ; U806.1@63.025,35.75 63.21,35.75 63.21,36.117 v2(63.25,36.157) ; U800.1@63.025,44.75 63.11,44.75 63.11,45.36 v2(63.15,45.4)
  Signal Layer 3 w0.3: v2@53.3,31.85 53.309,31.859 55.419,31.859 55.96,31.318 58.66,31.318 59.678,30.3 62.001,30.3 v1(62.986,29.315)
  Signal Layer 4 w0.3: v1(62.986,29.315) 62.382,29.919 62.382,32.095 62.875,32.588 62.875,33.725 62.55,34.05 62.55,35.457 v2(63.25,36.157) ; v2(63.15,45.4) 63.15,45.344 63.225,45.269 63.225,41.665 63.025,41.466 63.025,37.834 63.268,37.591 v2@63.268,36.218
VTARGET_BUF: C655.1 C806.1 L801.1 R636.2 R687.2 R801.2 R809.2 U808.23 U808.24 | length 86.2
  Top Layer w0.3: R636.2@41.275,29.2 41.275,29.19 41.285,29.18 41.285,28.754 41.457,28.582 v2(41.457,28.526) ; R687.2@49.35,25.625 49.95,25.625 50.605,26.28 51.095,26.28 C655.1@51.1,26.275 51.129,26.246 51.129,25.529 v2(51.157,25.5) ; v2(49.641,33.937) 49.687,33.937 50.25,34.5 50.3,34.5 50.5,34.7 R809.2@50.5,35.325 ; v2(54.4,47.75) C806.1@54.85,47.75 54.825,47.725 U808.24@54.825,46.745 55.68,46.745 55.87,46.555 U808.23@55.87,46.2 ; R801.2@58.514,43.782 58.516,43.785 58.979,43.785 59.144,43.95 v2(59.2,43.95)
  Signal Layer 3 w0.3: v2(43.575,25.875) 45.875,25.875 46.267,25.483 51.14,25.483 v2(51.157,25.5) ; v2@51.183,25.483 51.2,25.5 53.493,25.5 53.868,25.875 62.318,25.875 v2(62.675,26.232) ; v2(54.4,47.75) 54.44,47.71 54.587,47.71 54.59,47.707 55.916,47.707 56.309,48.1 59.093,48.1 59.425,47.768 v2(59.425,47.757) ; v2@59.437,47.745 60.309,48.616 67.149,48.616 v2(67.611,48.154)
  Signal Layer 4 w0.3: v2(41.457,28.526) 41.457,26.999 42.582,25.875 v2(43.575,25.875) ; v2(49.641,33.937) 49.605,33.901 49.605,33.247 51.474,31.377 51.474,25.817 v2(51.157,25.5) ; v2(59.2,43.95) 59.16,43.99 58.788,43.99 58.432,44.346 58.432,44.754 59.425,45.747 v2(59.425,47.757) ; v2(62.675,26.232) 63.754,26.232 67.194,29.672 67.194,38.654 67.308,38.768 67.308,40.283 68.425,41.4 68.425,47.341 v2(67.611,48.154)
VTARGET_SENSE: C638.1 R636.1 R637.2 U910.5 | length 2.7
  Top Layer w0.1: C638.1@40.175,29.775 40.188,29.787 40.713,29.787 R637.2@40.725,29.8 ; U910.5@40.3,31.025 40.625,31.025 40.725,30.925 R637.2@40.725,29.8 ; R636.1@41.275,29.8 R637.2@40.725,29.8
VTREF: Q800.4 R816.2 TPJ817.1 U800.2 | length 61.5
  Top Layer w0.3: Q800.4@58,37.55 58,37.045 58.21,36.835 58.21,36.721 58.375,36.556 v2(58.375,36.5) ; U800.2@62.575,45.7 62.575,46.55 R816.2@62.625,46.6 v2(62.626,47.271)
  Signal Layer 3 w0.3: v2(57.325,47.025) 60.372,47.025 60.618,47.271 v2(62.626,47.271) 63.248,47.893 65.941,47.893 66.197,47.637 69.413,47.637 ; 69.738,47.312 69.413,47.637 ; v1(94.1,48.3) 85.65,48.3 84.081,46.731 70.319,46.731 69.413,47.637
  Signal Layer 4 w0.3: v2(57.325,47.025) 57.286,46.986 57.286,41.409 58.843,39.852 58.843,38.573 58.375,38.105 v2(58.375,36.5)
  Bottom Layer w0.3: v1(94.1,48.3) 94.125,48.325 102.623,48.325 TPJ817.1@102.648,48.349
pads on no net: D400.3 D800.5 D801.1 J101.21 J101.22 J101.23 J102.11 M2.1 M3.1 P101.M1 P101.M2 P601.25@1.8,56.82 P601.26@1.8,48.18 P601.27@6.2,56.525 P601.27@6.85,56.82 P601.28@6.2,48.475 P601.28@6.85,48.18 P601.A2 P601.A3 P601.A8 P601.A10 P601.A11 P601.B2 P601.B3 P601.B8 P601.B10 P601.B11 P601.M1 P601.M2 P800.7 P800.11 P800.13 P801.10 P801.12 P801.14 P801.16 P801.18 P801.20 P801.M1 P801.M2 RP800.2 RP800.7 SW704.5 U600.8 U701.8 U800.17 U802.17 U806.17 U808.8 U808.9 U808.10 U810.17 U900.B11 U900.E12 U900.F12 U900.G2 U900.H2 U900.J2 U900.L3 U900.L8 U900.L12 U900.M4 U900.M12 U900.M13 U900.N7 U900.N12 U901.9 U902.C1
copper on no net: | length 0
  Bottom Layer w0.3: 54.675,41.125 54.693,41.143

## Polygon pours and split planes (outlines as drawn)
GND on Bottom Layer "GND_L8" (solid, remove dead copper, pour order 30): 0,0 0.175,60.15 120.175,60.15 120.175,0 30.7,0 30.7,9.4 60.7,9.4 60.7,18.4 30.7,18.4 30.7,0
GND on Bottom Layer "GND2_L8" (hatched 90Degree grid 1 track 0.203, pour order 33): 29.984,8.5 29.984,19.4 60.966,19.4 60.966,8.5
3V3 on Signal Layer 5 "3V3_L5" (solid, remove dead copper, pour order 25): 114.5,59.5 0.5,59.5 0.5,0.5 24,0.5 114.286,0.5
5V on Signal Layer 5 "5V_L5" (solid, remove dead copper, pour order 24): 22.5,51.881 24.111,53.492 65.992,53.492 68.5,56 70,56 72.468,53.532 102,53.493 102,59.538 19.538,59.538 16,56 11.5,56 11.5,55.975 9.508,55.975 8.503,54.97 8.503,50.092 18.144,40.452 24.711,33.885 30.598,33.885 34,30.483 34.983,30.483 36.307,31.938 36.307,34.694 36.65,35.037 36.65,39.13 33.305,42.475 24.881,42.475 24.66,42.696 24.66,45.267 22.5,47.427
VMCU on Signal Layer 5 "VMCU_L5" (solid, remove dead copper, pour order 23): 69.165,35.505 71.37,37.71 71.658,37.72 88.448,37.72 90.676,39.78 106.047,39.78 107,40.733 107,48.879 106.488,49.392 106.488,49.5 105.354,49.5 105.129,49.735 105.129,52.703 105.426,53 114.539,53 114.539,0.457 65.545,0.457 22.5,0.462 21.325,0.45 21.15,0.625 21.15,2.525 21.325,2.7 22.125,2.7 22.5,3.05 22.5,3.275 22.5,5 24.6,7.1 61.25,7.1 63.875,4.475 69.875,4.475 69.875,4.525 70.7,5.35 70.675,5.375 70.675,8.65 70.487,8.913 70.025,9.375 60.9,9.375 60.7,9.575 60.7,18.45 60.675,18.475 29.425,18.475 29,18.875 29,22.5 32.366,25.866 39.798,25.866 41.976,28 55.124,28 62.629,35.505
GND on Top Layer "GND_L1" (solid, remove dead copper, pour order 45): -0.15,0.125 -0.15,33.375 -0.15,60.125 119.85,60.125 119.85,0.125
VMCU_S on Top Layer "VMCU_S_L01_P027" (solid, remove dead copper, pour order 27): 27.504,30.213 28.089,30.213 28.188,30.312 28.188,30.933 28.377,31.122 28.912,31.122 29.709,30.325 31.527,30.325 31.527,31.752 31.461,31.818 30.817,31.818 30.817,32.201 30.585,32.433 30.297,32.433 30.297,32.391 29.866,31.96 29.329,31.96 29.071,32.219 27.705,32.219 27.486,32 27.486,30.227 27.491,30.227
3V3 on Top Layer "3V3_L01_P036" (solid, remove dead copper, pour order 36): 24.047,43.57 24.047,43.999 24.233,43.999 24.401,44.167 25.789,44.167 25.945,44.01 25.945,42.938 25.756,42.749 25.039,42.749 24.71,43.078 24.249,43.539 24.076,43.539 24.076,43.541
5V on Top Layer "5V_L01_P034" (solid, remove dead copper, pour order 34): 23.512,42.55 23.516,42.547 23.516,41.409 23.021,40.915 22.148,40.915 21.736,41.327 21.736,42.413 21.838,42.515 22.778,42.515 22.851,42.588 23.477,42.588 23.477,42.586 23.507,42.556 23.587,42.636 23.587,42.705
USBC_VBUS on Top Layer "USBC_VBUS_L01_P038" (solid, remove dead copper, pour order 38): 9.837,53.771 9.837,55.06 9.646,55.25 8.81,55.25 8.348,54.789 8.348,54.036 8.618,53.766 9.837,53.766
5V on Top Layer "5V_L01_P039" (solid, remove dead copper, pour order 39): 10.607,53.679 10.592,53.695 10.592,55.025 10.764,55.197 11.853,55.197 12.078,54.972 12.078,53.865 11.818,53.605 10.575,53.605 10.427,53.754
N17457715 on Top Layer "N17457715_L01_P040" (solid, remove dead copper, pour order 40): 72.801,9.344 72.5,9.043 72.5,8.898 72.289,8.898 72.13,9.057 72.13,9.291 72.02,9.4 72.02,10.981 72.127,11.088 72.275,11.088 72.859,10.504 72.859,9.611 72.859,9.485
5V on Top Layer "5V_L01_P041" (solid, remove dead copper, pour order 41): 69.473,12.017 69.42,12.069 67.617,12.069 67.077,11.529 67.077,9.306 67.392,8.991 67.394,8.993 68.698,8.993 68.698,10.36 69.619,11.281 69.619,11.919 69.521,12.017
EFM_USB_VBUS on Top Layer "EFM_USB_VBUS_L01_P042" (solid, remove dead copper, pour order 42): 72.275,6.93 72.275,6.388 73.023,5.641 74.365,5.641 74.508,5.784 74.508,6.894 72.32,6.894 72.387,6.827 72.387,6.801
GND on Signal Layer 4 "GND_L4" (solid, remove dead copper, pour order 37): 0,0 0,60 114.951,60 114.951,0
USBC_VBUS on Signal Layer 4 "USBC_VBUS_L04_P029" (solid, remove dead copper, pour order 29): 10.017,55.251 9.981,55.287 9.009,55.287 8.451,54.729 6.498,54.729 6.075,54.306 6.075,50.733 6.39,50.418 8.064,50.418 8.766,51.12 8.766,52.56 8.541,52.785 8.118,52.785 7.902,53.001 7.902,53.541 8.148,53.787 9.588,53.787 10.014,54.213 10.008,54.219 10.008,55.233
GND on Signal Layer 2 "GND_L2" (solid, remove dead copper, pour order 26): 0,0 0,60 120,60 120,0
GND on Signal Layer 3 "GND_L3" (solid, remove dead copper, pour order 28): 0,0 0,60 114.951,60 114.951,0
